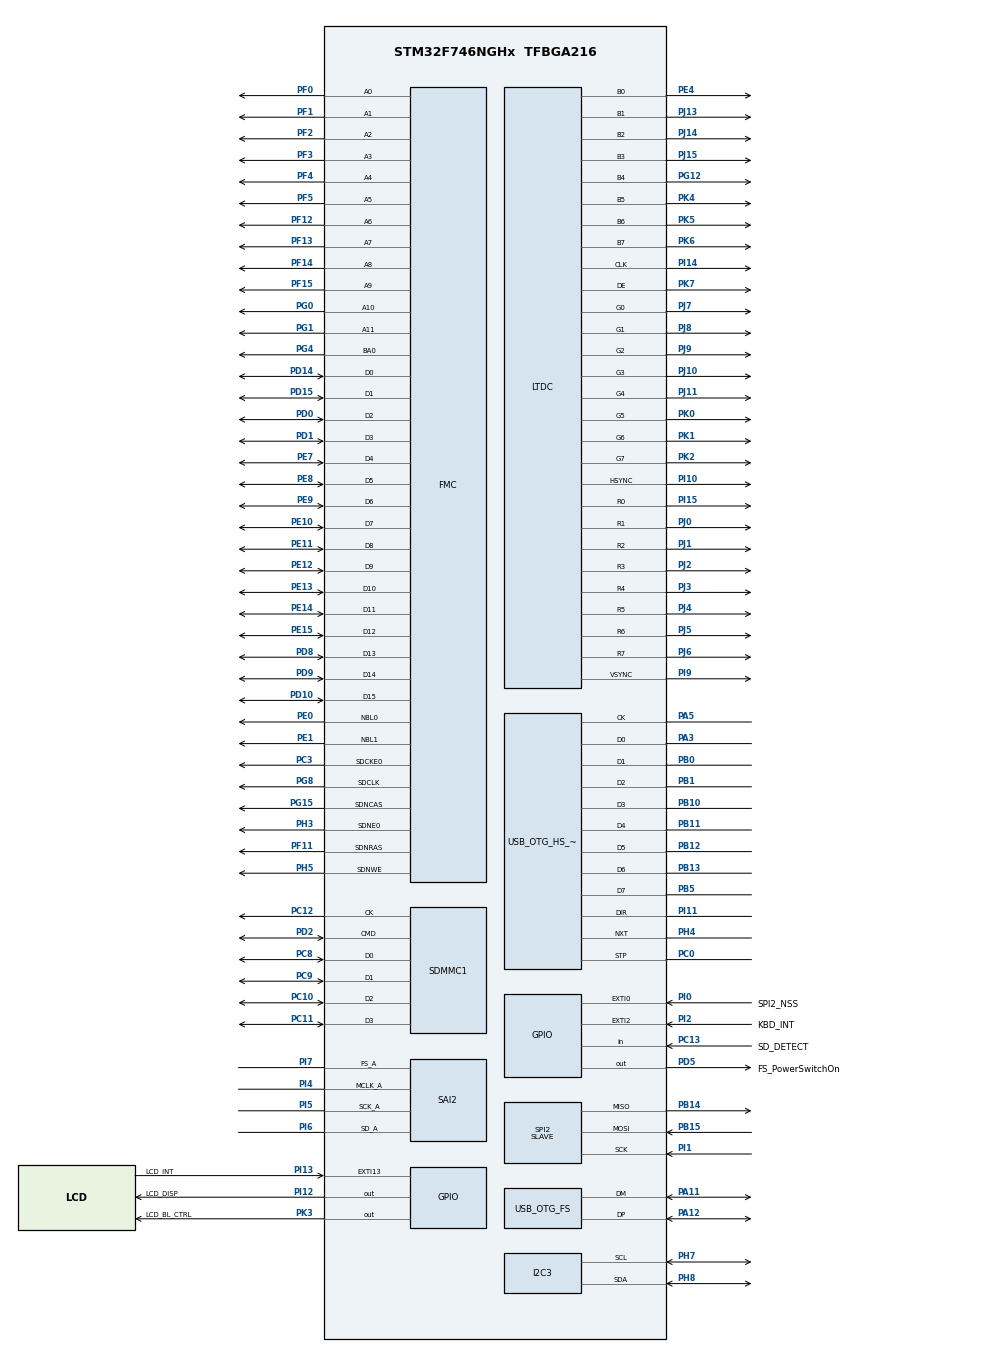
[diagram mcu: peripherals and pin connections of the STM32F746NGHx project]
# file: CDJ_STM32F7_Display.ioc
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CORTEX_M7.ART_ACCLERATOR_ENABLE=1
CORTEX_M7.CPU_DCache=Enabled
CORTEX_M7.CPU_ICache=Enabled
CORTEX_M7.MPU_Control=MPU_PRIVILEGED_DEFAULT
CORTEX_M7.PREFETCH_ENABLE=1
DMA2D.ColorMode=DMA2D_OUTPUT_RGB565
DMA2D.Mode=DMA2D_R2M
Dma.Request0=SAI2_A
Dma.SAI2_A.0.Direction=DMA_MEMORY_TO_PERIPH
Dma.SAI2_A.0.FIFOMode=DMA_FIFOMODE_DISABLE
Dma.SAI2_A.0.Instance=DMA2_Stream4
Dma.SAI2_A.0.MemDataAlignment=DMA_MDATAALIGN_HALFWORD
Dma.SAI2_A.0.MemInc=DMA_MINC_ENABLE
Dma.SAI2_A.0.Mode=DMA_CIRCULAR
Dma.SAI2_A.0.PeriphDataAlignment=DMA_PDATAALIGN_HALFWORD
Dma.SAI2_A.0.PeriphInc=DMA_PINC_DISABLE
Dma.SAI2_A.0.Priority=DMA_PRIORITY_LOW
FATFS._CODE_PAGE=866
FATFS._FS_EXFAT=1
FATFS._FS_LOCK=0
FATFS._FS_NORTC=1
FATFS._FS_READONLY=1
FATFS._LFN_UNICODE=1
FATFS._NORTC_MDAY=9
FATFS._NORTC_MON=5
FATFS._NORTC_YEAR=2018
FATFS._STRF_ENCODE=1
FATFS._USE_FASTSEEK=1
FATFS._USE_LFN=1
FATFS._USE_MKFS=0
FATFS._USE_STRFUNC=2
FMC.CASLatency1=FMC_SDRAM_CAS_LATENCY_2
FMC.ExitSelfRefreshDelay1=6
FMC.LoadToActiveDelay1=2
FMC.RCDDelay1=2
FMC.RPDelay1=2
FMC.ReadBurst1=FMC_SDRAM_RBURST_ENABLE
FMC.RowCycleDelay1=6
FMC.SDClockPeriod1=FMC_SDRAM_CLOCK_PERIOD_2
FMC.SelfRefreshTime1=4
FMC.WriteRecoveryTime1=2
I2C3.Timing=0x20303E5D
LTDC.ActiveH=272
LTDC.ActiveW=480
LTDC.Alpha_L0=0
LTDC.Alpha_L1=0
LTDC.BlendingFactor1_L0=LTDC_BLENDING_FACTOR1_CA
LTDC.BlendingFactor1_L1=LTDC_BLENDING_FACTOR1_CA
LTDC.BlendingFactor2_L0=LTDC_BLENDING_FACTOR2_CA
LTDC.BlendingFactor2_L1=LTDC_BLENDING_FACTOR2_CA
LTDC.HBP=43
LTDC.HFP=8
LTDC.HSync=1
LTDC.ImageHeight_L0=272
LTDC.ImageHeight_L1=272
LTDC.ImageWidth_L0=480
LTDC.ImageWidth_L1=480
LTDC.Layers=1
LTDC.PixelFormat_L0=LTDC_PIXEL_FORMAT_RGB565
LTDC.PixelFormat_L1=LTDC_PIXEL_FORMAT_RGB565
LTDC.VBP=20
LTDC.VFP=4
LTDC.VSync=10
LTDC.WindowX1_L0=480
LTDC.WindowX1_L1=480
LTDC.WindowY1_L0=272
LTDC.WindowY1_L1=272
Mcu.Family=STM32F7
Mcu.Name=STM32F746NGHx
Mcu.Package=TFBGA216
NVIC.DMA2_Stream4_IRQn=true\:0\:0\:false\:false\:true\:false\:true\:true
NVIC.EXTI0_IRQn=true\:2\:0\:true\:false\:true\:true\:true\:true
NVIC.EXTI15_10_IRQn=true\:3\:0\:true\:false\:true\:true\:true\:true
NVIC.EXTI2_IRQn=true\:2\:0\:true\:false\:true\:true\:true\:true
NVIC.OTG_FS_IRQn=true\:0\:0\:false\:false\:true\:false\:true\:true
NVIC.PriorityGroup=NVIC_PRIORITYGROUP_4
NVIC.SPI2_IRQn=true\:2\:0\:true\:false\:true\:true\:true\:true
NVIC.TIM1_BRK_TIM9_IRQn=true\:2\:0\:true\:false\:true\:true\:true\:true
NVIC.TIM4_IRQn=true\:1\:0\:true\:false\:true\:true\:true\:true
NVIC.TIM5_IRQn=true\:3\:0\:true\:false\:true\:true\:true\:true
NVIC.TIM6_DAC_IRQn=true\:1\:0\:true\:false\:true\:true\:true\:true
NVIC.TIM7_IRQn=true\:4\:0\:true\:false\:true\:true\:true\:true
NVIC.TIM8_UP_TIM13_IRQn=true\:1\:0\:true\:false\:true\:true\:true\:true
PA11.Mode=Host_Only
PA11.Signal=USB_OTG_FS_DM
PA12.Mode=Host_Only
PA12.Signal=USB_OTG_FS_DP
PA13.Mode=Serial_Wire
PA13.Signal=SYS_JTMS-SWDIO
PA14.Mode=Serial_Wire
PA14.Signal=SYS_JTCK-SWCLK
PA3.Mode=Host_HS
PA3.Signal=USB_OTG_HS_ULPI_D0
PA5.Mode=Host_HS
PA5.Signal=USB_OTG_HS_ULPI_CK
PB0.Mode=Host_HS
PB0.Signal=USB_OTG_HS_ULPI_D1
PB1.Mode=Host_HS
PB1.Signal=USB_OTG_HS_ULPI_D2
PB10.Mode=Host_HS
PB10.Signal=USB_OTG_HS_ULPI_D3
PB11.Mode=Host_HS
PB11.Signal=USB_OTG_HS_ULPI_D4
PB12.Mode=Host_HS
PB12.Signal=USB_OTG_HS_ULPI_D5
PB13.Mode=Host_HS
PB13.Signal=USB_OTG_HS_ULPI_D6
PB14.Mode=Full_Duplex_Slave
PB14.Signal=SPI2_MISO
PB15.Mode=Full_Duplex_Slave
PB15.Signal=SPI2_MOSI
PB5.Mode=Host_HS
PB5.Signal=USB_OTG_HS_ULPI_D7
PC0.Mode=Host_HS
PC0.Signal=USB_OTG_HS_ULPI_STP
PC10.Mode=SD_4_bits_Wide_bus
PC10.Signal=SDMMC1_D2
PC11.Mode=SD_4_bits_Wide_bus
PC11.Signal=SDMMC1_D3
PC12.Mode=SD_4_bits_Wide_bus
PC12.Signal=SDMMC1_CK
PC13.GPIO_Label=SD_DETECT
PC13.GPIO_PuPd=GPIO_PULLUP
PC13.Signal=GPIO_Input
PC3.Mode=SdramChipSelect1_1
PC3.Signal=FMC_SDCKE0
PC8.Mode=SD_4_bits_Wide_bus
PC8.Signal=SDMMC1_D0
PC9.Mode=SD_4_bits_Wide_bus
PC9.Signal=SDMMC1_D1
PD0.Signal=FMC_D2_DA2
PD1.Signal=FMC_D3_DA3
PD10.Signal=FMC_D15_DA15
PD14.Signal=FMC_D0_DA0
PD15.Signal=FMC_D1_DA1
PD2.Mode=SD_4_bits_Wide_bus
PD2.Signal=SDMMC1_CMD
PD5.GPIO_Label=FS_PowerSwitchOn
PD5.Signal=GPIO_Output
PD8.Signal=FMC_D13_DA13
PD9.Signal=FMC_D14_DA14
PE0.Signal=FMC_NBL0
PE1.Signal=FMC_NBL1
PE10.Signal=FMC_D7_DA7
PE11.Signal=FMC_D8_DA8
PE12.Signal=FMC_D9_DA9
PE13.Signal=FMC_D10_DA10
PE14.Signal=FMC_D11_DA11
PE15.Signal=FMC_D12_DA12
PE4.GPIO_Speed=GPIO_SPEED_FREQ_VERY_HIGH
PE4.Mode=RGB888
PE4.Signal=LTDC_B0
PE7.Signal=FMC_D4_DA4
PE8.Signal=FMC_D5_DA5
PE9.Signal=FMC_D6_DA6
PF0.Signal=FMC_A0
PF1.Signal=FMC_A1
PF11.Signal=FMC_SDNRAS
PF12.Signal=FMC_A6
PF13.Signal=FMC_A7
PF14.Signal=FMC_A8
PF15.Signal=FMC_A9
PF2.Signal=FMC_A2
PF3.Signal=FMC_A3
PF4.Signal=FMC_A4
PF5.Signal=FMC_A5
PG0.Signal=FMC_A10
PG1.Signal=FMC_A11
PG12.GPIO_Speed=GPIO_SPEED_FREQ_VERY_HIGH
PG12.Mode=RGB888
PG12.Signal=LTDC_B4
PG15.Signal=FMC_SDNCAS
PG4.Signal=FMC_A14_BA0
PG8.Signal=FMC_SDCLK
PH0/OSC_IN.Mode=HSE-External-Oscillator
PH0/OSC_IN.Signal=RCC_OSC_IN
PH1/OSC_OUT.Mode=HSE-External-Oscillator
PH1/OSC_OUT.Signal=RCC_OSC_OUT
PH3.Mode=SdramChipSelect1_1
PH3.Signal=FMC_SDNE0
PH4.Mode=Host_HS
PH4.Signal=USB_OTG_HS_ULPI_NXT
PH5.Signal=FMC_SDNWE
PH7.GPIO_Pu=GPIO_PULLUP
PH7.Mode=I2C
PH7.Signal=I2C3_SCL
PH8.GPIO_Pu=GPIO_PULLUP
PH8.Mode=I2C
PH8.Signal=I2C3_SDA
PI0.GPIO_Label=SPI2_NSS
PI0.GPIO_ModeDefaultEXTI=GPIO_MODE_IT_FALLING
PI0.GPIO_PuPd=GPIO_PULLUP
PI0.Signal=GPXTI0
PI1.Mode=Full_Duplex_Slave
PI1.Signal=SPI2_SCK
PI10.GPIO_Speed=GPIO_SPEED_FREQ_VERY_HIGH
PI10.Mode=RGB888
PI10.Signal=LTDC_HSYNC
PI11.Mode=Host_HS
PI11.Signal=USB_OTG_HS_ULPI_DIR
PI12.GPIO_Label=LCD_DISP
PI12.GPIO_Speed=GPIO_SPEED_FREQ_HIGH
PI12.PinState=GPIO_PIN_SET
PI12.Signal=GPIO_Output
PI13.GPIO_Label=LCD_INT
PI13.Signal=GPXTI13
PI14.GPIO_Speed=GPIO_SPEED_FREQ_VERY_HIGH
PI14.Mode=RGB888
PI14.Signal=LTDC_CLK
PI15.GPIO_Speed=GPIO_SPEED_FREQ_VERY_HIGH
PI15.Mode=RGB888
PI15.Signal=LTDC_R0
PI2.GPIO_Label=KBD_INT
PI2.Signal=GPXTI2
PI4.GPIO_Speed=GPIO_SPEED_FREQ_HIGH
PI4.Mode=SAI_A_MasterWithClock
PI4.Signal=SAI2_MCLK_A
PI5.GPIO_Speed=GPIO_SPEED_FREQ_HIGH
PI5.Mode=SAI_A_MasterWithClock
PI5.Signal=SAI2_SCK_A
PI6.GPIO_Speed=GPIO_SPEED_FREQ_HIGH
PI6.Mode=SAI_A_MasterWithClock
PI6.Signal=SAI2_SD_A
PI7.GPIO_Speed=GPIO_SPEED_FREQ_HIGH
PI7.Mode=SAI_A_MasterWithClock
PI7.Signal=SAI2_FS_A
PI9.GPIO_Speed=GPIO_SPEED_FREQ_VERY_HIGH
PI9.Mode=RGB888
PI9.Signal=LTDC_VSYNC
PJ0.GPIO_Speed=GPIO_SPEED_FREQ_VERY_HIGH
PJ0.Mode=RGB888
PJ0.Signal=LTDC_R1
PJ1.GPIO_Speed=GPIO_SPEED_FREQ_VERY_HIGH
PJ1.Mode=RGB888
PJ1.Signal=LTDC_R2
PJ10.GPIO_Speed=GPIO_SPEED_FREQ_VERY_HIGH
PJ10.Mode=RGB888
PJ10.Signal=LTDC_G3
PJ11.GPIO_Speed=GPIO_SPEED_FREQ_VERY_HIGH
PJ11.Mode=RGB888
PJ11.Signal=LTDC_G4
PJ13.GPIO_Speed=GPIO_SPEED_FREQ_VERY_HIGH
PJ13.Mode=RGB888
PJ13.Signal=LTDC_B1
PJ14.GPIO_Speed=GPIO_SPEED_FREQ_VERY_HIGH
PJ14.Mode=RGB888
PJ14.Signal=LTDC_B2
PJ15.GPIO_Speed=GPIO_SPEED_FREQ_VERY_HIGH
PJ15.Mode=RGB888
PJ15.Signal=LTDC_B3
PJ2.GPIO_Speed=GPIO_SPEED_FREQ_VERY_HIGH
PJ2.Mode=RGB888
PJ2.Signal=LTDC_R3
PJ3.GPIO_Speed=GPIO_SPEED_FREQ_VERY_HIGH
PJ3.Mode=RGB888
PJ3.Signal=LTDC_R4
PJ4.GPIO_Speed=GPIO_SPEED_FREQ_VERY_HIGH
PJ4.Mode=RGB888
PJ4.Signal=LTDC_R5
PJ5.GPIO_Speed=GPIO_SPEED_FREQ_VERY_HIGH
PJ5.Mode=RGB888
PJ5.Signal=LTDC_R6
PJ6.GPIO_Speed=GPIO_SPEED_FREQ_VERY_HIGH
PJ6.Mode=RGB888
PJ6.Signal=LTDC_R7
PJ7.GPIO_Speed=GPIO_SPEED_FREQ_VERY_HIGH
PJ7.Mode=RGB888
PJ7.Signal=LTDC_G0
PJ8.GPIO_Speed=GPIO_SPEED_FREQ_VERY_HIGH
PJ8.Mode=RGB888
PJ8.Signal=LTDC_G1
PJ9.GPIO_Speed=GPIO_SPEED_FREQ_VERY_HIGH
PJ9.Mode=RGB888
PJ9.Signal=LTDC_G2
PK0.GPIO_Speed=GPIO_SPEED_FREQ_VERY_HIGH
PK0.Mode=RGB888
PK0.Signal=LTDC_G5
PK1.GPIO_Speed=GPIO_SPEED_FREQ_VERY_HIGH
PK1.Mode=RGB888
PK1.Signal=LTDC_G6
PK2.GPIO_Speed=GPIO_SPEED_FREQ_VERY_HIGH
PK2.Mode=RGB888
PK2.Signal=LTDC_G7
PK3.GPIO_Label=LCD_BL_CTRL
PK3.GPIO_Speed=GPIO_SPEED_FREQ_HIGH
PK3.PinState=GPIO_PIN_SET
PK3.Signal=GPIO_Output
PK4.GPIO_Speed=GPIO_SPEED_FREQ_VERY_HIGH
PK4.Mode=RGB888
PK4.Signal=LTDC_B5
PK5.GPIO_Speed=GPIO_SPEED_FREQ_VERY_HIGH
PK5.Mode=RGB888
PK5.Signal=LTDC_B6
PK6.GPIO_Speed=GPIO_SPEED_FREQ_VERY_HIGH
PK6.Mode=RGB888
PK6.Signal=LTDC_B7
PK7.GPIO_Speed=GPIO_SPEED_FREQ_VERY_HIGH
PK7.Mode=RGB888
PK7.Signal=LTDC_DE
ProjectManager.HeapSize=0x200
ProjectManager.StackSize=0x400
ProjectManager.TargetToolchain=STM32CubeIDE
RCC.AHBFreq_Value=192000000
RCC.APB1CLKDivider=RCC_HCLK_DIV4
RCC.APB1Freq_Value=48000000
RCC.APB1TimFreq_Value=96000000
RCC.APB2CLKDivider=RCC_HCLK_DIV2
RCC.APB2Freq_Value=96000000
RCC.APB2TimFreq_Value=192000000
RCC.CortexFreq_Value=192000000
RCC.HCLKFreq_Value=192000000
RCC.HSE_VALUE=25000000
RCC.HSI_VALUE=16000000
RCC.LSE_VALUE=32768
RCC.PLLI2SN=100
RCC.PLLM=25
RCC.PLLN=384
RCC.PLLQ=8
RCC.PLLSAIN=240
RCC.PLLSAIP=RCC_PLLSAIP_DIV6
RCC.PLLSAIR=6
RCC.PLLSAIRDiv=RCC_PLLSAIDIVR_4
RCC.SAI2CLockSelection=RCC_SAI2CLKSOURCE_PLLI2S
RCC.SDMMCClockSelection=RCC_SDMMC1CLKSOURCE_CLK48
RCC.SYSCLKFreq_VALUE=192000000
RCC.SYSCLKSource=RCC_SYSCLKSOURCE_PLLCLK
RCC.USBFreq_Value=48000000
RCC.VCOOutputFreq_Value=384000000
SAI2.ActiveFrameLength-SAI_A_MasterWithClock=32
SAI2.AudioFrequency-SAI_A_MasterWithClock=SAI_AUDIO_FREQUENCY_48K
SAI2.ClockStrobing-SAI_A_MasterWithClock=SAI_CLOCKSTROBING_RISINGEDGE
SAI2.DataSize-SAI_A_MasterWithClock=SAI_DATASIZE_16
SAI2.ErrorAudioFreq-SAI_A_MasterWithClock=1.72 %
SAI2.FIFOThreshold-SAI_A_MasterWithClock=SAI_FIFOTHRESHOLD_1QF
SAI2.FSDefinition-SAI_A_MasterWithClock=SAI_FS_CHANNEL_IDENTIFICATION
SAI2.FSOffset-SAI_A_MasterWithClock=SAI_FS_BEFOREFIRSTBIT
SAI2.FrameLength-SAI_A_MasterWithClock=64
SAI2.Instance-SAI_A_MasterWithClock=SAI$Index_Block_A
SAI2.MClockEnable-SAI_A_MasterWithClock=SAI_MASTERCLOCK_ENABLE
SAI2.NoDivider-SAI_A_MasterWithClock=SAI_MASTERDIVIDER_ENABLE
SAI2.OutputDrive-SAI_A_MasterWithClock=SAI_OUTPUTDRIVE_ENABLE
SAI2.RealAudioFreq-SAI_A_MasterWithClock=48.828 KHz
SAI2.SlotActive-SAI_A_MasterWithClock=0x0000000F
SAI2.SlotNumber-SAI_A_MasterWithClock=4
SAI2.Synchro-SAI_A_MasterWithClock=SAI_ASYNCHRONOUS
SAI2.SynchroExt-SAI_A_MasterWithClock=SAI_SYNCEXT_DISABLE
SAI2.VirtualMode-SAI_A_MasterWithClock=VM_MASTER
SAI2.VirtualSlotActive-SAI_A_MasterWithClock=SAI_SLOT_USERSETTING
SAI2.VirtualSlotActive0-SAI_A_MasterWithClock=true
SAI2.VirtualSlotActive1-SAI_A_MasterWithClock=true
SAI2.VirtualSlotActive2-SAI_A_MasterWithClock=true
SAI2.VirtualSlotActive3-SAI_A_MasterWithClock=true
SDMMC1.ClockDiv=2
SDMMC1.ClockEdge=SDMMC_CLOCK_EDGE_RISING
SDMMC1.HardwareFlowControl=SDMMC_HARDWARE_FLOW_CONTROL_ENABLE
SH.FMC_A0.0=FMC_A0,12b-sda1
SH.FMC_A1.0=FMC_A1,12b-sda1
SH.FMC_A10.0=FMC_A10,12b-sda1
SH.FMC_A11.0=FMC_A11,12b-sda1
SH.FMC_A14_BA0.0=FMC_BA0,TwoSdramBanks1
SH.FMC_A2.0=FMC_A2,12b-sda1
SH.FMC_A3.0=FMC_A3,12b-sda1
SH.FMC_A4.0=FMC_A4,12b-sda1
SH.FMC_A5.0=FMC_A5,12b-sda1
SH.FMC_A6.0=FMC_A6,12b-sda1
SH.FMC_A7.0=FMC_A7,12b-sda1
SH.FMC_A8.0=FMC_A8,12b-sda1
SH.FMC_A9.0=FMC_A9,12b-sda1
SH.FMC_D0_DA0.0=FMC_D0,sd-16b-d1
SH.FMC_D10_DA10.0=FMC_D10,sd-16b-d1
SH.FMC_D11_DA11.0=FMC_D11,sd-16b-d1
SH.FMC_D12_DA12.0=FMC_D12,sd-16b-d1
SH.FMC_D13_DA13.0=FMC_D13,sd-16b-d1
SH.FMC_D14_DA14.0=FMC_D14,sd-16b-d1
SH.FMC_D15_DA15.0=FMC_D15,sd-16b-d1
SH.FMC_D1_DA1.0=FMC_D1,sd-16b-d1
SH.FMC_D2_DA2.0=FMC_D2,sd-16b-d1
SH.FMC_D3_DA3.0=FMC_D3,sd-16b-d1
SH.FMC_D4_DA4.0=FMC_D4,sd-16b-d1
SH.FMC_D5_DA5.0=FMC_D5,sd-16b-d1
SH.FMC_D6_DA6.0=FMC_D6,sd-16b-d1
SH.FMC_D7_DA7.0=FMC_D7,sd-16b-d1
SH.FMC_D8_DA8.0=FMC_D8,sd-16b-d1
SH.FMC_D9_DA9.0=FMC_D9,sd-16b-d1
SH.FMC_NBL0.0=FMC_NBL0,Sd2ByteEnable1
SH.FMC_NBL1.0=FMC_NBL1,Sd2ByteEnable1
SH.FMC_SDCLK.0=FMC_SDCLK,12b-sda1
SH.FMC_SDNCAS.0=FMC_SDNCAS,12b-sda1
SH.FMC_SDNRAS.0=FMC_SDNRAS,12b-sda1
SH.FMC_SDNWE.0=FMC_SDNWE,12b-sda1
SPI2.CLKPhase=SPI_PHASE_2EDGE
SPI2.CLKPolarity=SPI_POLARITY_HIGH
SPI2.DataSize=SPI_DATASIZE_8BIT
SPI2.Direction=SPI_DIRECTION_2LINES
SPI2.Mode=SPI_MODE_SLAVE
SPI2.VirtualType=VM_SLAVE
TIM4.Period=399
TIM4.Prescaler=9999
TIM5.Period=1999
TIM5.Prescaler=19199
TIM6.Period=999
TIM6.Prescaler=9999
TIM7.Period=4999
TIM7.Prescaler=9999
TIM8.Period=9999
TIM8.Prescaler=9599
TIM9.Period=19999
TIM9.Prescaler=9599
USB_HOST.BSP.number=1
USB_HOST.USBH_HandleTypeDef-MSC_FS=hUsbHostFS
USB_HOST.VirtualModeFS=Msc
USB_HOST0.BSP.STBoard=false
USB_HOST0.BSP.api=Unknown
USB_HOST0.BSP.instance=PD5
USB_HOST0.BSP.ip=GPIO
USB_HOST0.BSP.mode=Output
USB_HOST0.BSP.name=Drive_VBUS_FS
USB_HOST0.BSP.solution=PD5
USB_OTG_FS.VirtualMode=Host_Only
USB_OTG_FS.phy_itface=HCD_PHY_EMBEDDED
USB_OTG_HS.VirtualMode-Host_HS=Host_HS
VP_DMA2D_VS_DMA2D.Mode=DMA2D_Activate
VP_FATFS_VS_USB.Mode=USB
VP_TIM4_VS_ClockSourceINT.Mode=Internal
VP_TIM5_VS_ClockSourceINT.Mode=Internal
VP_TIM6_VS_ClockSourceINT.Mode=Enable_Timer
VP_TIM7_VS_ClockSourceINT.Mode=Enable_Timer
VP_TIM8_VS_ClockSourceINT.Mode=Internal
VP_TIM9_VS_ClockSourceINT.Mode=Internal
VP_USB_HOST_VS_USB_HOST_MSC_FS.Mode=MSC_FS
board=Display

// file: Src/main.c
/* USER CODE BEGIN Header */
/**
  ******************************************************************************
  * @file           : main.c
  * @brief          : Main program body
  ******************************************************************************
  * This notice applies to any and all portions of this file
  * that are not between comment pairs USER CODE BEGIN and
  * USER CODE END. Other portions of this file, whether
  * inserted by the user or by software development tools
  * are owned by their respective copyright owners.
  *
  * Copyright (c) 2018 STMicroelectronics International N.V.
  * All rights reserved.
  *
  * Redistribution and use in source and binary forms, with or without
  * modification, are permitted, provided that the following conditions are met:
  *
  * 1. Redistribution of source code must retain the above copyright notice,
  *    this list of conditions and the following disclaimer.
  * 2. Redistributions in binary form must reproduce the above copyright notice,
  *    this list of conditions and the following disclaimer in the documentation
  *    and/or other materials provided with the distribution.
  * 3. Neither the name of STMicroelectronics nor the names of other
  *    contributors to this software may be used to endorse or promote products
  *    derived from this software without specific written permission.
  * 4. This software, including modifications and/or derivative works of this
  *    software, must execute solely and exclusively on microcontroller or
  *    microprocessor devices manufactured by or for STMicroelectronics.
  * 5. Redistribution and use of this software other than as permitted under
  *    this license is void and will automatically terminate your rights under
  *    this license.
  *
  * THIS SOFTWARE IS PROVIDED BY STMICROELECTRONICS AND CONTRIBUTORS "AS IS"
  * AND ANY EXPRESS, IMPLIED OR STATUTORY WARRANTIES, INCLUDING, BUT NOT
  * LIMITED TO, THE IMPLIED WARRANTIES OF MERCHANTABILITY, FITNESS FOR A
  * PARTICULAR PURPOSE AND NON-INFRINGEMENT OF THIRD PARTY INTELLECTUAL PROPERTY
  * RIGHTS ARE DISCLAIMED TO THE FULLEST EXTENT PERMITTED BY LAW. IN NO EVENT
  * SHALL STMICROELECTRONICS OR CONTRIBUTORS BE LIABLE FOR ANY DIRECT, INDIRECT,
  * INCIDENTAL, SPECIAL, EXEMPLARY, OR CONSEQUENTIAL DAMAGES (INCLUDING, BUT NOT
  * LIMITED TO, PROCUREMENT OF SUBSTITUTE GOODS OR SERVICES; LOSS OF USE, DATA,
  * OR PROFITS; OR BUSINESS INTERRUPTION) HOWEVER CAUSED AND ON ANY THEORY OF
  * LIABILITY, WHETHER IN CONTRACT, STRICT LIABILITY, OR TORT (INCLUDING
  * NEGLIGENCE OR OTHERWISE) ARISING IN ANY WAY OUT OF THE USE OF THIS SOFTWARE,
  * EVEN IF ADVISED OF THE POSSIBILITY OF SUCH DAMAGE.
  *
  ******************************************************************************
  */
/* USER CODE END Header */
#include "main.h"
#include "dma.h"
#include "dma2d.h"
#include "fatfs.h"
#include "i2c.h"
#include "ltdc.h"
#include "sai.h"
#include "sdmmc.h"
#include "spi.h"
#include "tim.h"
#include "usb_host.h"
#include "gpio.h"
#include "fmc.h"

/* USER CODE BEGIN Includes */
#include <string.h>
#include <wchar.h>
#include "rekordbox.h"
#include "display.h"
#include "mp3dec.h"
#include "stm32746g_discovery_audio.h"
#include "stm32746g_discovery_ts.h"
#include "waveplayer.h"
#include "mp3player.h"
#include "ff.h"
/* USER CODE END Includes */

/* USER CODE BEGIN PV */
/* Private variables ---------------------------------------------------------*/
uint8_t ActiveLayer = 0;
int Track_number = 0;
FATFS SDFatFs;  /* File system object for SD card logical drive */
FATFS USBHFatFs;  /* File system object for USB_Host logical drive */
FIL MyFile;     /* File object */
extern char SDPath[4]; /* SD card logical drive path */
extern char USBHPath[4]; /* USB Host logical drive path */
//extern ApplicationTypeDef Appli_HS_state;
extern ApplicationTypeDef Appli_FS_state;
FRESULT res;
DIR dir;
static FILINFO fno;
TCHAR new_path[255] = {0};
TCHAR old_path[255] = {0};
uint16_t bytesread = 0;
uint32_t file_pos = 0;
uint32_t file_pos_wide = 0;
extern volatile int32_t position;
uint8_t lowp_wavebuffer[400];
extern RekordboxTypeDef rekordbox;
extern DisplayTypeDef display;
uint16_t Total_tracks = 0;
char TrackTable[MAXTOTALTRACKS][255];
char TrackPaths[MAXTOTALTRACKS][255];
int8_t halffr = 0;
int16_t fr = 0;
int8_t sec = 0;
int8_t min = 0;
int16_t rfr = 0;
int8_t rsec = 0;
int8_t rmin = 0;
uint8_t tim7_flag = 0;
extern int8_t menu_mode;
extern int beat;
extern int bar;

//volatile uint16_t* lcdLocFramebuffer0; //[400*272];
//volatile uint16_t* lcdLocFramebuffer1; //[400*272];
//uint8_t* waveBuffer;  //[MAX_WAVESIZE];

uint8_t spi_tx[4] = {0x08, 0x90, 0xFF, 0x00};
uint8_t spi_rx[4] = {0};

TrackTypeDef trak;

HMP3Decoder	hMP3Decoder;

TS_StateTypeDef ts_State;

AUDIO_OUT_BufferTypeDef BufferCtl;

volatile UINT bOutOfData = 0;
volatile uint32_t unDmaBufMode = 0;
uint8_t volume = 60;
uint8_t acue_sensitivity = 30;
/* USER CODE END PV */

void SystemClock_Config(void);
static void MPU_Config(void);
void MX_USB_HOST_Process(FATFS* USBHfs, TCHAR const* USBHPath);

/* USER CODE BEGIN PFP */
/* Private function prototypes -----------------------------------------------*/
FRESULT scan_files();
FRESULT find_file(uint16_t track_number);

/* USER CODE END PFP */

/*************************************
 *
 *
 * ***************
 * *** FIXED  ****
 * ***************
 *
 * setting WCHAR (src alias for TCHAR) to 'unsigned int' WORKS!   (instead of 'unsigned short')
 * in ' Middleware/Third_Party/Fatfs/src/integer.h '
 *
 * ********************
 *
 *  wchar problems with and without compiler flags: -fshort-wchar
 *
 *  without constructors create UTF32 wchars /  L"text" == _T("text")   /  also, the 32bit TCHARs are not compatible with the FATFS functions
 *
 *  with the flags the constructors are UTF16 but the wcscpy / wcscat still UTF32 (linked from prebuild toolchain) and messes up the memory
 *
 *
 ********************************/

int main(void)
{

  /* MPU Configuration--------------------------------------------------------*/
  MPU_Config();

  /* Enable I-Cache---------------------------------------------------------*/
  SCB_EnableICache();

  /* Enable D-Cache---------------------------------------------------------*/
  SCB_EnableDCache();

  /* MCU Configuration--------------------------------------------------------*/

  /* Reset of all peripherals, Initializes the Flash interface and the Systick. */
  HAL_Init();

  /* Configure the system clock */
  SystemClock_Config();

  /* Initialize all configured peripherals */
  MX_GPIO_Init();
  MX_DMA_Init();
  MX_LTDC_Init();
  MX_FMC_Init();
  MX_SDMMC1_SD_Init();
  MX_FATFS_Init();
  MX_DMA2D_Init();
  MX_SAI2_Init();
  MX_I2C3_Init();
  MX_TIM4_Init();
  MX_TIM6_Init();
  MX_TIM7_Init();
  MX_TIM8_Init();
  MX_SPI2_Init();
  MX_TIM5_Init();
  MX_TIM9_Init();
  /* USER CODE BEGIN 2 */
  SDRAM_Init(); // MT48LC4M32B2B5-6A SDRAM initialization
  menu_mode=3;

  HAL_LTDC_SetAddress(&hltdc, LCD_FB_START_ADDRESS_0, 0); // set layer 0 framebuffer address
  HAL_LTDC_SetAddress(&hltdc, LCD_FB_START_ADDRESS_1, 1); // set layer 1 framebuffer address
     //HAL_LTDC_SetAddress(&hltdc, (uint32_t)lcdLocFramebuffer0, 0); // set layer 0 framebuffer address
     //HAL_LTDC_SetAddress(&hltdc, (uint32_t)lcdLocFramebuffer1, 1); // set layer 1 framebuffer address
  ClearLayer(); // clear framebuffer 0
  BSP_LCD_DisplayOn();

  MX_USB_HOST_Init();

  HAL_TIM_Base_Start_IT(&htim4); // start display refresh timer

  HAL_LTDC_SetAlpha_NoReload(&hltdc, 0, ActiveLayer++);
  HAL_LTDC_SetAlpha_NoReload(&hltdc, 255, ActiveLayer--);
  ChangeLayers();
  ClearLayer(); // clear framebuffer 1
  dbgAddText("pre init");

  MX_USB_HOST_Process(&USBHFatFs, (const TCHAR*)USBHPath);
 // while(1){}; //HALT

  dbgAddText("host init");
  while(((BSP_SD_IsDetected() != SD_PRESENT))&&(Appli_FS_state != APPLICATION_READY)){   //&&(Appli_FS_state != APPLICATION_START))   {
	  menu_mode = 3;
	  BSP_LCD_DisplayOn();
	  MX_USB_HOST_Process(&USBHFatFs, (const TCHAR*)USBHPath);
	  //HAL_Delay(2000);
  }
  dbgAddText("post usb");

  BSP_TS_Init(480, 272); // touchscreen initialization
  BSP_TS_ITClear();
  BSP_TS_ITConfig();
  if (BSP_SD_IsDetected() == SD_PRESENT){
	  dbgAddText("sd present");
  	  f_mount(&SDFatFs, (const TCHAR*)SDPath, 0); // SD card disk mount
  }
  else if ((Appli_FS_state != APPLICATION_READY)) //&& (Appli_FS_state != APPLICATION_START))   //shouldn't be true if it got here, but just to be safe  --- USB already mounts
  {
	  menu_mode = 3;
	  BSP_LCD_DisplayOn();
	  MX_USB_HOST_Process(&USBHFatFs, (const TCHAR*)USBHPath);
	  dbgAddText("usb halt");
	  while(1);
  }
  else if (Appli_FS_state == APPLICATION_READY)	//mount USB
  {
  	  f_mount(&USBHFatFs, (const TCHAR*)USBHPath, 0); // USB disk mount
  }

  hMP3Decoder = MP3InitDecoder(); // mp3 decoder initialization

  dbgAddText("pre scan");
  scan_files(); // get total track number
  dbgAddText("post scan");

  HAL_TIM_Base_Start_IT(&htim5); // start jog speed counting timer
  HAL_SPI_TransmitReceive_IT(&hspi2, spi_tx, spi_rx, 4);
  BSP_AUDIO_OUT_Init(OUTPUT_DEVICE_HEADPHONE, volume, (uint32_t)(AUDIO_FREQUENCY_22K)*(1 + trak.percent));
  BSP_AUDIO_OUT_SetVolume(0);
  BSP_LCD_DisplayOn();
  /* USER CODE END 2 */

  /* Infinite loop */
  /* USER CODE BEGIN WHILE */
  while (1)
  {
	  find_file(Track_number);
	  fr = 0;
	  sec = 0;
	  min = 0;
	  rfr = 0;
	  rsec = 0;
	  rmin = 0;
	  file_pos_wide = 0;
	  position = 0;
	  rekordbox.state = 0;
	  display.loop = 0;
	  if(display.cuemode == 1) rekordbox.autocue = 1;
	  else rekordbox.autocue = 0;
	  rekordbox.currentcue = 0;
	  DecodeRekordboxFiles(new_path);
	  menu_mode = 0;
	  bar = 0;
	  beat = 0;
	  res = f_open(&MyFile, rekordbox.filename, FA_READ);
	  if(res == FR_OK)
	  {
		  trak.state = PLAYING;
		  spi_tx[2] &= ~(1 << 0);
		  if(rekordbox.autocue == 2) spi_tx[2] &= ~(1 << 1);
		  else spi_tx[2] |= (1 << 1);
		  spi_tx[2] &= ~(1 << 3);
		  if((strcmp(rekordbox.filetype, ".wav") == 0) || (strcmp(rekordbox.filetype, ".WAV") == 0)) {
			  PlayWavFile();
		  }
		  if((strcmp(rekordbox.filetype, ".mp3") == 0) || (strcmp(rekordbox.filetype, ".MP3") == 0)) {
			  PlayMp3File();
		  }
		  spi_tx[2] |= (1 << 3);
		  trak.state = STOPPED;
		  BSP_AUDIO_OUT_Stop(CODEC_PDWN_SW);
	  }
	  if(file_pos_wide >= rekordbox.spectrum_size) {
		  Track_number++;
	  }
	  file_pos_wide = 0;
	  menu_mode = 4;
	  f_close(&MyFile);
	  f_closedir(&dir);
	  if(Track_number >= Total_tracks) Track_number = 0;
	  if(Track_number < 0) Track_number = Total_tracks - 1;

	  MX_USB_HOST_Process(&USBHFatFs, (const TCHAR*)USBHPath);
  }
    /* USER CODE END WHILE */
  MX_USB_HOST_Process(&USBHFatFs, (const TCHAR*)USBHPath);

}

void SystemClock_Config(void)
{
  RCC_OscInitTypeDef RCC_OscInitStruct = {0};
  RCC_ClkInitTypeDef RCC_ClkInitStruct = {0};
  RCC_PeriphCLKInitTypeDef PeriphClkInitStruct;

  /** Configure the main internal regulator output voltage
  */
  __HAL_RCC_PWR_CLK_ENABLE();
  __HAL_PWR_VOLTAGESCALING_CONFIG(PWR_REGULATOR_VOLTAGE_SCALE1);

  /** Initializes the RCC Oscillators according to the specified parameters
  * in the RCC_OscInitTypeDef structure.
  */
  RCC_OscInitStruct.OscillatorType = RCC_OSCILLATORTYPE_HSE;
  RCC_OscInitStruct.HSEState = RCC_HSE_ON;
  RCC_OscInitStruct.HSIState = RCC_HSI_OFF;
  RCC_OscInitStruct.PLL.PLLState = RCC_PLL_ON;
  RCC_OscInitStruct.PLL.PLLSource = RCC_PLLSOURCE_HSE;
  RCC_OscInitStruct.PLL.PLLM = 25;
  RCC_OscInitStruct.PLL.PLLN = 400;//384;
  RCC_OscInitStruct.PLL.PLLP = RCC_PLLP_DIV2;
  RCC_OscInitStruct.PLL.PLLQ = 8;
  if (HAL_RCC_OscConfig(&RCC_OscInitStruct) != HAL_OK)
  {
    Error_Handler();
  }

  /** Activate the Over-Drive mode
  */
  if (HAL_PWREx_EnableOverDrive() != HAL_OK)
  {
    Error_Handler();
  }

  /* Select PLLSAI output as USB clock source */
  PeriphClkInitStruct.PeriphClockSelection = RCC_PERIPHCLK_CLK48;
  PeriphClkInitStruct.Clk48ClockSelection = RCC_CLK48SOURCE_PLLSAIP;
  PeriphClkInitStruct.PLLSAI.PLLSAIN = 192;
  PeriphClkInitStruct.PLLSAI.PLLSAIQ = 4;
  PeriphClkInitStruct.PLLSAI.PLLSAIP = RCC_PLLSAIP_DIV4;
  if (HAL_RCCEx_PeriphCLKConfig(&PeriphClkInitStruct) != HAL_OK)
  {
    Error_Handler();
  }

  /* Select PLL as system clock source and configure the HCLK, PCLK1 and PCLK2
   * clocks dividers */
  RCC_ClkInitStruct.ClockType =
    (RCC_CLOCKTYPE_SYSCLK | RCC_CLOCKTYPE_HCLK | RCC_CLOCKTYPE_PCLK1 |
     RCC_CLOCKTYPE_PCLK2);
  RCC_ClkInitStruct.SYSCLKSource = RCC_SYSCLKSOURCE_PLLCLK;
  RCC_ClkInitStruct.AHBCLKDivider = RCC_SYSCLK_DIV1;
  RCC_ClkInitStruct.APB1CLKDivider = RCC_HCLK_DIV4;
  RCC_ClkInitStruct.APB2CLKDivider = RCC_HCLK_DIV2;
  if (HAL_RCC_ClockConfig(&RCC_ClkInitStruct, FLASH_LATENCY_6) != HAL_OK)
  {
    Error_Handler();
  }
}

/* USER CODE BEGIN 4 */
FRESULT scan_files()
{
    DIR folder;
    UINT i = 0;
    UINT folders = 0;
    UINT subfolders = 0;
    TCHAR relative_path[255] = {0};
    //TCHAR pio_dir[20] = {0};
    //wcscpy(pio_dir,L"/PIONEER/USBANLZ/"+'\0'+'\0');
    while(1) {
    	res = f_opendir(&folder, L"/PIONEER/USBANLZ");	/* Open the directory */
    	if (res != FR_OK) {
    		break;	/* Break on error or no dir */
    	}
    	i = 0;
    	do {
    		res = f_readdir(&folder, &fno);	/* Read a new, unknown directory item */
    	}while(i++ < folders);

    	if ((res != FR_OK) || (fno.fname[0] == '\0') || (Total_tracks>=MAXTOTALTRACKS)) {
    		f_closedir(&folder);
    		break;	/* Break on error or end of dir */
    	}
    	if (fno.fattrib & AM_DIR) {	/* It is a directory */
    		folders++;
    		for(i = 0; i < 255; i++) new_path[i] = 0;		//clr new_path
    		wcscpy(new_path, L"/PIONEER/USBANLZ/");

    		for(i = 0; i < 255; i++) relative_path[i] = 0;	//clr rel_path
    		wcscpy(relative_path, fno.fname);				//rel_path= [directory]

    		wcscat(new_path, relative_path);					//step in new_path=  /PIONEER/USBANLZ/ + [directory]
    		wcscpy(old_path, new_path);						//old_path=new_path
    		f_closedir(&folder);
    		subfolders = 0;
    		while(1) {
    			res = f_opendir(&folder, old_path);			//we have to go deeper
    			for(i = 0; i < 255; i++) new_path[i] = 0;	//clr new_path
    			wcscpy(new_path, old_path);					//re-use new_path=  /PIONEER/USBANLZ/ + [directory]
    			i = 0;
    			do {
    				res = f_readdir(&folder, &fno);	/* Read a new directory item */
    			}while(i++ < subfolders);

    			if ((res != FR_OK) || (fno.fname[0] == '\0') || (Total_tracks>=MAXTOTALTRACKS)) {
    				f_closedir(&folder);
    				break;  /* Break on error or end of dir */
    			}
    			if (fno.fattrib & AM_DIR) {	/* It is a directory */
    				subfolders++;
    				wcscat(new_path, L"/");
    				wcscat(new_path, fno.fname);			// new_path=  /PIONEER/USBANLZ/ + [directory] + /[subdir]
    				//wcscat(relative_path, L"/");
    				//wcscat(relative_path, fno.fname);		// rel_path= [directory] + /[subdir]
    				f_closedir(&folder);
    				res = f_opendir(&folder, new_path);		//one more level deeper
    				if(res == FR_OK) {
    					res = f_readdir(&folder, &fno);		//there should be files!
    					if (!(fno.fattrib & AM_DIR)) {
    						for(i=0; i<255; i++) TrackPaths[Total_tracks][i] = ff_convert(new_path[i], 0);		//populate database
    						wcscat(new_path, L"/");
    						wcscat(new_path, fno.fname);			//one of the files --- does not matter -- all starts with the main header then the mediafile
    						if (GetFileName(new_path)==0)		//filename OK -- otherwise tracknumber overwritten with usable one (hopefully)
    						{
    							for(i = 0; i < 255; i++) TrackTable[Total_tracks][i] = rekordbox.file[i];
    							Total_tracks++;
    						}
							f_closedir(&folder);
    					}
    				}
    			}
    		}
    	}
    }
    return res;
}

FRESULT find_file(uint16_t track_number)
{
    DIR folder;
    TCHAR path[255] = {0};
    for(int i=0; i<255; i++) path[i] = ff_convert(TrackPaths[Track_number][i], 1);
    wcscpy(new_path, path);
	res = f_opendir(&folder, new_path);
	if(res == FR_OK) {
		res = f_readdir(&folder, &fno);
		if (!(fno.fattrib & AM_DIR)) {
		}
	}
    return res;
}

/* USER CODE END 4 */

/* MPU Configuration */

void MPU_Config(void)
{
  MPU_Region_InitTypeDef MPU_InitStruct;

  /* Disables the MPU */
  HAL_MPU_Disable();

  /* Configure the MPU as Strongly ordered for not defined regions */
  MPU_InitStruct.Enable = MPU_REGION_ENABLE;
  MPU_InitStruct.BaseAddress = 0x00;
  MPU_InitStruct.Size = MPU_REGION_SIZE_4GB;
  MPU_InitStruct.AccessPermission = MPU_REGION_NO_ACCESS;
  MPU_InitStruct.IsBufferable = MPU_ACCESS_NOT_BUFFERABLE;
  MPU_InitStruct.IsCacheable = MPU_ACCESS_NOT_CACHEABLE;
  MPU_InitStruct.IsShareable = MPU_ACCESS_SHAREABLE;
  MPU_InitStruct.Number = MPU_REGION_NUMBER0;
  MPU_InitStruct.TypeExtField = MPU_TEX_LEVEL0;
  MPU_InitStruct.SubRegionDisable = 0x87;
  MPU_InitStruct.DisableExec = MPU_INSTRUCTION_ACCESS_DISABLE;

  HAL_MPU_ConfigRegion(&MPU_InitStruct);

  /* Configure the MPU attributes for SDRAM as WT */
  MPU_InitStruct.Enable = MPU_REGION_ENABLE;
  MPU_InitStruct.BaseAddress = 0xC0000000;
  MPU_InitStruct.Size = MPU_REGION_SIZE_8MB;
  MPU_InitStruct.AccessPermission = MPU_REGION_FULL_ACCESS;
  MPU_InitStruct.IsBufferable = MPU_ACCESS_NOT_BUFFERABLE;
  MPU_InitStruct.IsCacheable = MPU_ACCESS_CACHEABLE;
  MPU_InitStruct.IsShareable = MPU_ACCESS_NOT_SHAREABLE;
  MPU_InitStruct.Number = MPU_REGION_NUMBER1;
  MPU_InitStruct.TypeExtField = MPU_TEX_LEVEL0;
  MPU_InitStruct.SubRegionDisable = 0x00;
  MPU_InitStruct.DisableExec = MPU_INSTRUCTION_ACCESS_ENABLE;

  HAL_MPU_ConfigRegion(&MPU_InitStruct);

  /* Configure the MPU attributes FMC control registers */
  MPU_InitStruct.Enable = MPU_REGION_ENABLE;
  MPU_InitStruct.BaseAddress = 0xA0000000;
  MPU_InitStruct.Size = MPU_REGION_SIZE_8KB;
  MPU_InitStruct.AccessPermission = MPU_REGION_FULL_ACCESS;
  MPU_InitStruct.IsBufferable = MPU_ACCESS_BUFFERABLE;
  MPU_InitStruct.IsCacheable = MPU_ACCESS_NOT_CACHEABLE;
  MPU_InitStruct.IsShareable = MPU_ACCESS_SHAREABLE;
  MPU_InitStruct.Number = MPU_REGION_NUMBER2;
  MPU_InitStruct.TypeExtField = MPU_TEX_LEVEL0;
  MPU_InitStruct.SubRegionDisable = 0x0;
  MPU_InitStruct.DisableExec = MPU_INSTRUCTION_ACCESS_DISABLE;

  HAL_MPU_ConfigRegion(&MPU_InitStruct);

  /* Enables the MPU */
  HAL_MPU_Enable(MPU_PRIVILEGED_DEFAULT);

}

void Error_Handler(void)
{
  while(1)
  {
  }
}
